VERSION 5.7 ;
  NOWIREEXTENSIONATPIN ON ;
  DIVIDERCHAR "/" ;
  BUSBITCHARS "[]" ;
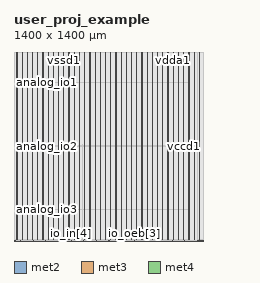
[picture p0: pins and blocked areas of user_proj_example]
MACRO user_proj_example
  CLASS BLOCK ;
  FOREIGN user_proj_example ;
  ORIGIN 0.000 0.000 ;
  SIZE 1400.000 BY 1400.000 ;
  PIN SEL2
    DIRECTION INPUT ;
    USE SIGNAL ;
    ANTENNAGATEAREA 0.247500 ;
    PORT
      LAYER met2 ;
        RECT 513.910 0.000 514.190 4.000 ;
    END
  END SEL2
  PIN analog_io1
    DIRECTION INOUT ;
    USE SIGNAL ;
    ANTENNADIFFAREA 0.434700 ;
    PORT
      LAYER met3 ;
        RECT 0.000 1165.560 4.000 1166.160 ;
    END
  END analog_io1
  PIN analog_io2
    DIRECTION INOUT ;
    USE SIGNAL ;
    ANTENNADIFFAREA 0.434700 ;
    PORT
      LAYER met3 ;
        RECT 0.000 699.080 4.000 699.680 ;
    END
  END analog_io2
  PIN analog_io3
    DIRECTION INOUT ;
    USE SIGNAL ;
    ANTENNADIFFAREA 0.434700 ;
    PORT
      LAYER met3 ;
        RECT 0.000 232.600 4.000 233.200 ;
    END
  END analog_io3
  PIN io_in[0]
    DIRECTION INPUT ;
    USE SIGNAL ;
    ANTENNAGATEAREA 0.159000 ;
    PORT
      LAYER met2 ;
        RECT 49.310 0.000 49.590 4.000 ;
    END
  END io_in[0]
  PIN io_in[1]
    DIRECTION INPUT ;
    USE SIGNAL ;
    ANTENNAGATEAREA 0.213000 ;
    PORT
      LAYER met2 ;
        RECT 142.230 0.000 142.510 4.000 ;
    END
  END io_in[1]
  PIN io_in[2]
    DIRECTION INPUT ;
    USE SIGNAL ;
    ANTENNAGATEAREA 0.213000 ;
    PORT
      LAYER met2 ;
        RECT 235.150 0.000 235.430 4.000 ;
    END
  END io_in[2]
  PIN io_in[3]
    DIRECTION INPUT ;
    USE SIGNAL ;
    ANTENNAGATEAREA 0.213000 ;
    PORT
      LAYER met2 ;
        RECT 328.070 0.000 328.350 4.000 ;
    END
  END io_in[3]
  PIN io_in[4]
    DIRECTION INPUT ;
    USE SIGNAL ;
    ANTENNAGATEAREA 0.426000 ;
    PORT
      LAYER met2 ;
        RECT 420.990 0.000 421.270 4.000 ;
    END
  END io_in[4]
  PIN io_oeb[0]
    DIRECTION OUTPUT TRISTATE ;
    USE SIGNAL ;
    PORT
      LAYER met2 ;
        RECT 606.830 0.000 607.110 4.000 ;
    END
  END io_oeb[0]
  PIN io_oeb[1]
    DIRECTION OUTPUT TRISTATE ;
    USE SIGNAL ;
    PORT
      LAYER met2 ;
        RECT 699.750 0.000 700.030 4.000 ;
    END
  END io_oeb[1]
  PIN io_oeb[2]
    DIRECTION OUTPUT TRISTATE ;
    USE SIGNAL ;
    PORT
      LAYER met2 ;
        RECT 792.670 0.000 792.950 4.000 ;
    END
  END io_oeb[2]
  PIN io_oeb[3]
    DIRECTION OUTPUT TRISTATE ;
    USE SIGNAL ;
    PORT
      LAYER met2 ;
        RECT 885.590 0.000 885.870 4.000 ;
    END
  END io_oeb[3]
  PIN io_oeb[4]
    DIRECTION OUTPUT TRISTATE ;
    USE SIGNAL ;
    PORT
      LAYER met2 ;
        RECT 978.510 0.000 978.790 4.000 ;
    END
  END io_oeb[4]
  PIN io_oeb[5]
    DIRECTION OUTPUT TRISTATE ;
    USE SIGNAL ;
    PORT
      LAYER met2 ;
        RECT 1071.430 0.000 1071.710 4.000 ;
    END
  END io_oeb[5]
  PIN io_oeb[6]
    DIRECTION OUTPUT TRISTATE ;
    USE SIGNAL ;
    PORT
      LAYER met2 ;
        RECT 1164.350 0.000 1164.630 4.000 ;
    END
  END io_oeb[6]
  PIN io_oeb[7]
    DIRECTION OUTPUT TRISTATE ;
    USE SIGNAL ;
    PORT
      LAYER met2 ;
        RECT 1257.270 0.000 1257.550 4.000 ;
    END
  END io_oeb[7]
  PIN io_oeb[8]
    DIRECTION OUTPUT TRISTATE ;
    USE SIGNAL ;
    PORT
      LAYER met2 ;
        RECT 1350.190 0.000 1350.470 4.000 ;
    END
  END io_oeb[8]
  PIN vccd1
    DIRECTION INOUT ;
    USE POWER ;
    PORT
      LAYER met4 ;
        RECT 21.040 10.640 22.640 1387.440 ;
    END
    PORT
      LAYER met4 ;
        RECT 174.640 10.640 176.240 1387.440 ;
    END
    PORT
      LAYER met4 ;
        RECT 328.240 10.640 329.840 1387.440 ;
    END
    PORT
      LAYER met4 ;
        RECT 481.840 10.640 483.440 1387.440 ;
    END
    PORT
      LAYER met4 ;
        RECT 635.440 10.640 637.040 1387.440 ;
    END
    PORT
      LAYER met4 ;
        RECT 789.040 10.640 790.640 1387.440 ;
    END
    PORT
      LAYER met4 ;
        RECT 942.640 10.640 944.240 1387.440 ;
    END
    PORT
      LAYER met4 ;
        RECT 1096.240 10.640 1097.840 1387.440 ;
    END
    PORT
      LAYER met4 ;
        RECT 1249.840 10.640 1251.440 1387.440 ;
    END
  END vccd1
  PIN vdda1
    DIRECTION INOUT ;
    USE POWER ;
    PORT
      LAYER met4 ;
        RECT 97.840 10.640 99.440 1387.440 ;
    END
    PORT
      LAYER met4 ;
        RECT 251.440 10.640 253.040 1387.440 ;
    END
    PORT
      LAYER met4 ;
        RECT 405.040 10.640 406.640 1387.440 ;
    END
    PORT
      LAYER met4 ;
        RECT 558.640 10.640 560.240 1387.440 ;
    END
    PORT
      LAYER met4 ;
        RECT 712.240 10.640 713.840 1387.440 ;
    END
    PORT
      LAYER met4 ;
        RECT 865.840 10.640 867.440 1387.440 ;
    END
    PORT
      LAYER met4 ;
        RECT 1019.440 10.640 1021.040 1387.440 ;
    END
    PORT
      LAYER met4 ;
        RECT 1173.040 10.640 1174.640 1387.440 ;
    END
    PORT
      LAYER met4 ;
        RECT 1326.640 10.640 1328.240 1387.440 ;
    END
  END vdda1
  PIN vssa1
    DIRECTION INOUT ;
    USE GROUND ;
    PORT
      LAYER met4 ;
        RECT 136.240 10.640 137.840 1387.440 ;
    END
    PORT
      LAYER met4 ;
        RECT 289.840 10.640 291.440 1387.440 ;
    END
    PORT
      LAYER met4 ;
        RECT 443.440 10.640 445.040 1387.440 ;
    END
    PORT
      LAYER met4 ;
        RECT 597.040 10.640 598.640 1387.440 ;
    END
    PORT
      LAYER met4 ;
        RECT 750.640 10.640 752.240 1387.440 ;
    END
    PORT
      LAYER met4 ;
        RECT 904.240 10.640 905.840 1387.440 ;
    END
    PORT
      LAYER met4 ;
        RECT 1057.840 10.640 1059.440 1387.440 ;
    END
    PORT
      LAYER met4 ;
        RECT 1211.440 10.640 1213.040 1387.440 ;
    END
    PORT
      LAYER met4 ;
        RECT 1365.040 10.640 1366.640 1387.440 ;
    END
  END vssa1
  PIN vssd1
    DIRECTION INOUT ;
    USE GROUND ;
    PORT
      LAYER met4 ;
        RECT 59.440 10.640 61.040 1387.440 ;
    END
    PORT
      LAYER met4 ;
        RECT 213.040 10.640 214.640 1387.440 ;
    END
    PORT
      LAYER met4 ;
        RECT 366.640 10.640 368.240 1387.440 ;
    END
    PORT
      LAYER met4 ;
        RECT 520.240 10.640 521.840 1387.440 ;
    END
    PORT
      LAYER met4 ;
        RECT 673.840 10.640 675.440 1387.440 ;
    END
    PORT
      LAYER met4 ;
        RECT 827.440 10.640 829.040 1387.440 ;
    END
    PORT
      LAYER met4 ;
        RECT 981.040 10.640 982.640 1387.440 ;
    END
    PORT
      LAYER met4 ;
        RECT 1134.640 10.640 1136.240 1387.440 ;
    END
    PORT
      LAYER met4 ;
        RECT 1288.240 10.640 1289.840 1387.440 ;
    END
    PORT
      LAYER met4 ;
        RECT 26.340 16.080 27.940 723.760 ;
    END
  END vssd1
  OBS
      LAYER li1 ;
        RECT 5.520 10.795 1394.260 1387.285 ;
      LAYER met1 ;
        RECT 5.520 10.640 1394.260 1387.440 ;
      LAYER met2 ;
        RECT 17.110 4.280 1350.920 1387.385 ;
        RECT 17.110 4.000 49.030 4.280 ;
        RECT 49.870 4.000 141.950 4.280 ;
        RECT 142.790 4.000 234.870 4.280 ;
        RECT 235.710 4.000 327.790 4.280 ;
        RECT 328.630 4.000 420.710 4.280 ;
        RECT 421.550 4.000 513.630 4.280 ;
        RECT 514.470 4.000 606.550 4.280 ;
        RECT 607.390 4.000 699.470 4.280 ;
        RECT 700.310 4.000 792.390 4.280 ;
        RECT 793.230 4.000 885.310 4.280 ;
        RECT 886.150 4.000 978.230 4.280 ;
        RECT 979.070 4.000 1071.150 4.280 ;
        RECT 1071.990 4.000 1164.070 4.280 ;
        RECT 1164.910 4.000 1256.990 4.280 ;
        RECT 1257.830 4.000 1349.910 4.280 ;
        RECT 1350.750 4.000 1350.920 4.280 ;
      LAYER met3 ;
        RECT 4.000 1166.560 1289.830 1387.365 ;
        RECT 4.400 1165.160 1289.830 1166.560 ;
        RECT 4.000 700.080 1289.830 1165.160 ;
        RECT 4.400 698.680 1289.830 700.080 ;
        RECT 4.000 233.600 1289.830 698.680 ;
        RECT 4.400 232.200 1289.830 233.600 ;
        RECT 4.000 10.715 1289.830 232.200 ;
      LAYER met4 ;
        RECT 504.455 11.735 507.545 708.385 ;
  END
END user_proj_example
END LIBRARY

